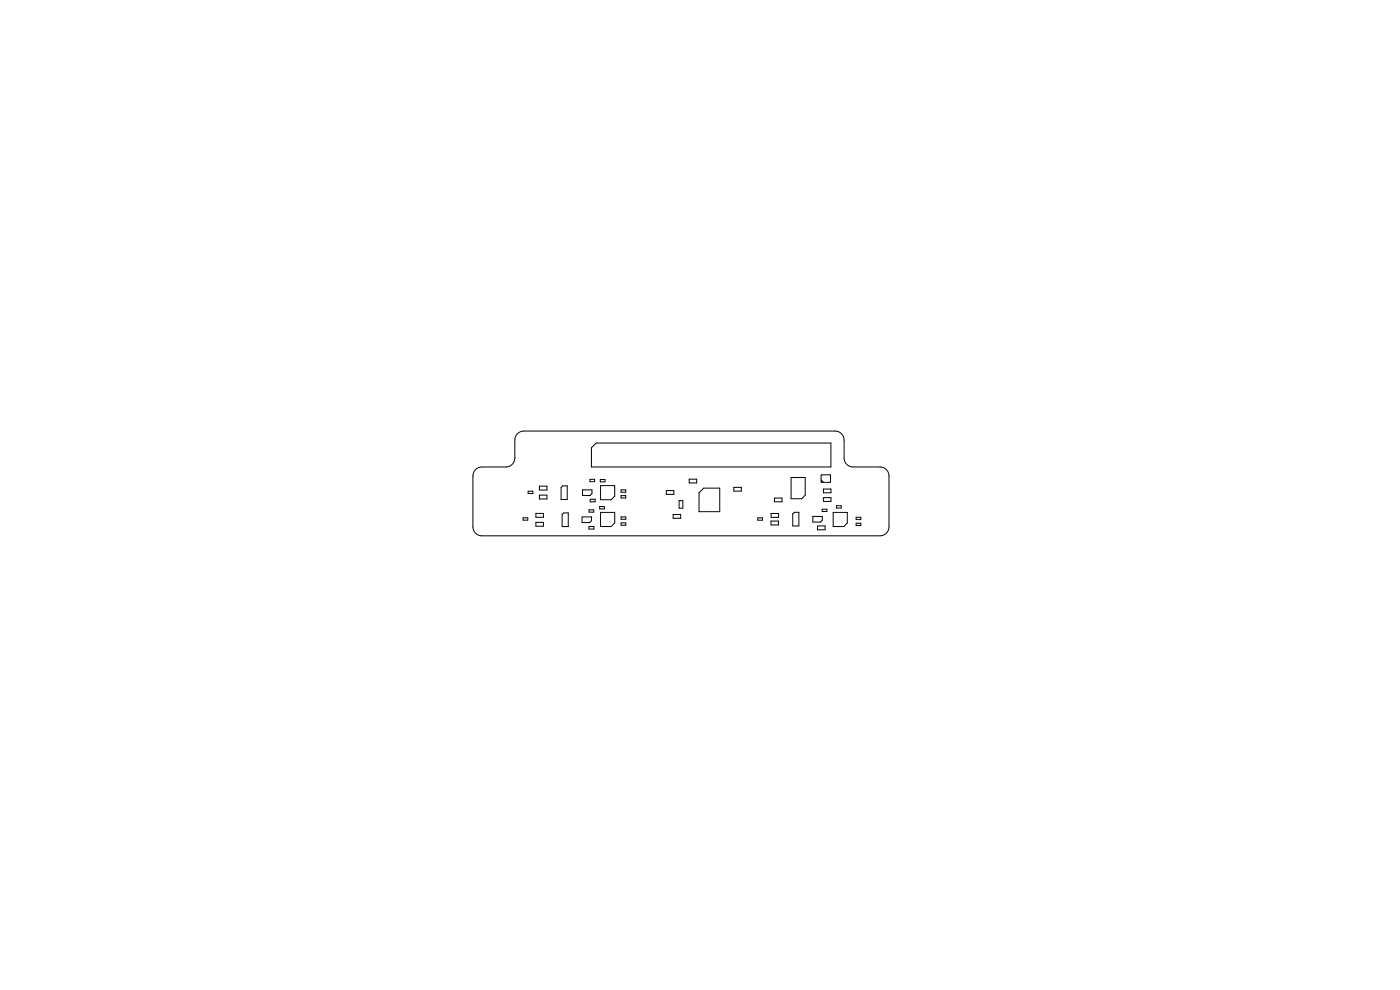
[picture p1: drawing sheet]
<svg xmlns="http://www.w3.org/2000/svg" width="297mm" height="210mm" viewBox="0 0 297 210" stroke-linecap="round" stroke-linejoin="round" font-family="sans-serif">
<g fill="none" stroke="#000" stroke-width=".21">
<path d="M100.8 99.7l.7-.5 .5-.1h5.3a1.9 1.9 0 0 0 1.9-1.9v-3.9a1.9 1.9 0 0 1 1.9-1.9h66.1a1.9 1.9 0 0 1 1.9 1.9v3.9a1.9 1.9 0 0 0 1.9 1.9h5.7a1.9 1.9 0 0 1 1.9 1.9v10.8a1.9 1.9 0 0 1-1.9 1.9h-84.5a1.9 1.9 0 0 1-1.9-1.9v-10.8l.1-.6zM125.5 95l1-1h49.8v5.1h-50.8zM111 109.8h1v.5h-1zM112 104.2h1v.5h-1zM113.7 108.9h1.6v.8h-1.6zM113.7 110.8h1.6v.8h-1.6zM114.4 103.1h1.6v.8h-1.6zM114.4 105h1.6v.9h-1.6zM119 103.4l.4-.3h.9v2.9h-1.3zM119.3 109.1l.3-.3h1v2.9h-1.3zM123.5 109.7h2v.8l-.4 .4h-1.6zM123.6 103.9h2v.8l-.4 .4h-1.6z"/>
<path d="M124.9 111.7h1.1v.5h-1.1zM125 108.1h1v.5h-1zM125.1 101.7h1v.5h-1zM125.2 105.9h1.1v.6h-1.1zM127.2 107.5h1v.5h-1zM127.3 101.7h1v.5h-1zM127.4 108.7h3v2.2l-.7 .8h-2.3zM127.4 103h3v2.3l-.7 .7h-2.3zM131.7 105.1h1v.5h-1zM131.8 110.9h1v.5h-1zM131.8 103.9h1v.5h-1zM131.8 109.7h1v.4h-1z"/>
<path d="M141.4 104.1h1.6v.8h-1.6zM142.8 109.1h1.6v.8h-1.6zM144.1 106.2h.8v1.6h-.8zM146.2 101.6h1.6v.8h-1.6zM148.3 104.5l1-1h3.4v5h-4.4zM155.7 103.4h1.6v.8h-1.6zM160.8 109.8h1v.5h-1zM163.6 110.5h1.6v.9h-1.6zM163.6 108.9h1.6v.8h-1.6zM164.3 105.6h1.6v.8h-1.6zM167.8 101.3h3v3.8l-.7 .7h-2.3zM168.5 108.7h1v2.9h-1.3v-2.6z"/>
<path d="M172.4 109.5h2v.9l-.4 .3h-1.6zM173.4 111.6h1.6v.8h-1.6zM174.2 100.8l1.9-.1 .1 1.5-1.9 .1zM174.2 101.8l.5 .5M174.4 108h1v.5h-1zM174.7 103.7h1.6v.8h-1.6zM174.7 105.6h1.6v.8h-1.6zM176.8 108.7h3v2.2l-.8 .8h-2.2zM177.5 107.3h1v.5h-1zM181.6 109.7h1v.5h-1zM181.6 111h1v.5h-1z"/>
</g>
</svg>
